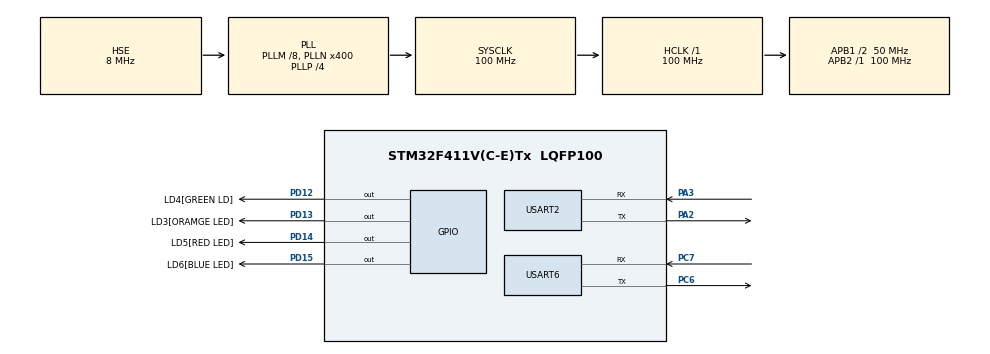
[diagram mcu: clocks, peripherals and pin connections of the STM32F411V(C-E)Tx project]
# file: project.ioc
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Dma.Request0=USART2_RX
Dma.Request1=USART2_TX
Dma.USART2_RX.0.Direction=DMA_PERIPH_TO_MEMORY
Dma.USART2_RX.0.FIFOMode=DMA_FIFOMODE_DISABLE
Dma.USART2_RX.0.Instance=DMA1_Stream5
Dma.USART2_RX.0.MemDataAlignment=DMA_MDATAALIGN_BYTE
Dma.USART2_RX.0.MemInc=DMA_MINC_ENABLE
Dma.USART2_RX.0.Mode=DMA_NORMAL
Dma.USART2_RX.0.PeriphDataAlignment=DMA_PDATAALIGN_BYTE
Dma.USART2_RX.0.PeriphInc=DMA_PINC_DISABLE
Dma.USART2_RX.0.Priority=DMA_PRIORITY_LOW
Dma.USART2_TX.1.Direction=DMA_MEMORY_TO_PERIPH
Dma.USART2_TX.1.FIFOMode=DMA_FIFOMODE_DISABLE
Dma.USART2_TX.1.Instance=DMA1_Stream6
Dma.USART2_TX.1.MemDataAlignment=DMA_MDATAALIGN_BYTE
Dma.USART2_TX.1.MemInc=DMA_MINC_ENABLE
Dma.USART2_TX.1.Mode=DMA_NORMAL
Dma.USART2_TX.1.PeriphDataAlignment=DMA_PDATAALIGN_BYTE
Dma.USART2_TX.1.PeriphInc=DMA_PINC_DISABLE
Dma.USART2_TX.1.Priority=DMA_PRIORITY_LOW
Mcu.Family=STM32F4
Mcu.Name=STM32F411V(C-E)Tx
Mcu.Package=LQFP100
NVIC.DMA1_Stream5_IRQn=true\:0\:0\:false\:false\:true\:false
NVIC.DMA1_Stream6_IRQn=true\:0\:0\:false\:false\:true\:false
NVIC.PriorityGroup=NVIC_PRIORITYGROUP_0
NVIC.USART2_IRQn=true\:0\:0\:false\:false\:true\:true
NVIC.USART6_IRQn=true\:0\:0\:false\:false\:true\:true
PA2.Mode=Asynchronous
PA2.Signal=USART2_TX
PA3.Mode=Asynchronous
PA3.Signal=USART2_RX
PC6.Mode=Asynchronous
PC6.Signal=USART6_TX
PC7.Mode=Asynchronous
PC7.Signal=USART6_RX
PD12.GPIO_Label=LD4[GREEN LD]
PD12.Signal=GPIO_Output
PD13.GPIO_Label=LD3[ORAMGE LED]
PD13.Signal=GPIO_Output
PD14.GPIO_Label=LD5[RED LED]
PD14.Signal=GPIO_Output
PD15.GPIO_Label=LD6[BLUE LED]
PD15.Signal=GPIO_Output
PH0\ -\ OSC_IN.Mode=HSE-External-Oscillator
PH0\ -\ OSC_IN.Signal=RCC_OSC_IN
PH1\ -\ OSC_OUT.Mode=HSE-External-Oscillator
PH1\ -\ OSC_OUT.Signal=RCC_OSC_OUT
ProjectManager.HeapSize=0x200
ProjectManager.StackSize=0x400
ProjectManager.TargetToolchain=Other Toolchains (GPDSC)
RCC.48MHZClocksFreq_Value=50000000
RCC.AHBFreq_Value=100000000
RCC.APB1CLKDivider=RCC_HCLK_DIV2
RCC.APB1Freq_Value=50000000
RCC.APB1TimFreq_Value=100000000
RCC.APB2Freq_Value=100000000
RCC.APB2TimFreq_Value=100000000
RCC.CortexFreq_Value=100000000
RCC.HCLKFreq_Value=100000000
RCC.HSE_VALUE=8000000
RCC.HSI_VALUE=16000000
RCC.LSE_VALUE=32768
RCC.PLLI2SM=5
RCC.PLLI2SN=200
RCC.PLLM=8
RCC.PLLN=400
RCC.PLLP=RCC_PLLP_DIV4
RCC.PLLQ=8
RCC.PLLSourceVirtual=RCC_PLLSOURCE_HSE
RCC.SYSCLKFreq_VALUE=100000000
RCC.SYSCLKSource=RCC_SYSCLKSOURCE_PLLCLK
RCC.VCOOutputFreq_Value=400000000
USART2.VirtualMode=VM_ASYNC
USART6.VirtualMode=VM_ASYNC
board=STM32F411E-DISCO

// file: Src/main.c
/**
  ******************************************************************************
  * File Name          : main.c
  * Description        : Main program body
  ******************************************************************************
  ** This notice applies to any and all portions of this file
  * that are not between comment pairs USER CODE BEGIN and
  * USER CODE END. Other portions of this file, whether
  * inserted by the user or by software development tools
  * are owned by their respective copyright owners.
  *
  * COPYRIGHT(c) 2017 STMicroelectronics
  *
  * Redistribution and use in source and binary forms, with or without modification,
  * are permitted provided that the following conditions are met:
  *   1. Redistributions of source code must retain the above copyright notice,
  *      this list of conditions and the following disclaimer.
  *   2. Redistributions in binary form must reproduce the above copyright notice,
  *      this list of conditions and the following disclaimer in the documentation
  *      and/or other materials provided with the distribution.
  *   3. Neither the name of STMicroelectronics nor the names of its contributors
  *      may be used to endorse or promote products derived from this software
  *      without specific prior written permission.
  *
  * THIS SOFTWARE IS PROVIDED BY THE COPYRIGHT HOLDERS AND CONTRIBUTORS "AS IS"
  * AND ANY EXPRESS OR IMPLIED WARRANTIES, INCLUDING, BUT NOT LIMITED TO, THE
  * IMPLIED WARRANTIES OF MERCHANTABILITY AND FITNESS FOR A PARTICULAR PURPOSE ARE
  * DISCLAIMED. IN NO EVENT SHALL THE COPYRIGHT HOLDER OR CONTRIBUTORS BE LIABLE
  * FOR ANY DIRECT, INDIRECT, INCIDENTAL, SPECIAL, EXEMPLARY, OR CONSEQUENTIAL
  * DAMAGES (INCLUDING, BUT NOT LIMITED TO, PROCUREMENT OF SUBSTITUTE GOODS OR
  * SERVICES; LOSS OF USE, DATA, OR PROFITS; OR BUSINESS INTERRUPTION) HOWEVER
  * CAUSED AND ON ANY THEORY OF LIABILITY, WHETHER IN CONTRACT, STRICT LIABILITY,
  * OR TORT (INCLUDING NEGLIGENCE OR OTHERWISE) ARISING IN ANY WAY OUT OF THE USE
  * OF THIS SOFTWARE, EVEN IF ADVISED OF THE POSSIBILITY OF SUCH DAMAGE.
  *
  ******************************************************************************
  */

#include "main.h"
#include "stm32f4xx_hal.h"
#include "GSM_7100.h"
#include "UARTXinOu.h"

UART_HandleTypeDef huart1;
UART_HandleTypeDef huart2;
UART_HandleTypeDef huart6;
DMA_HandleTypeDef hdma_usart2_rx;
DMA_HandleTypeDef hdma_usart2_tx;

/* USER CODE BEGIN PV */
/* Private variables ---------------------------------------------------------*/
#define		_AT_										"AT\r"
#define  temperature1 "EdgeFS1/1wire/temperature/th1"
#define  temperature2 "EdgeFS1/1wire/temperature/th2"

char pub = 123;

char ClientID[] = "EdgeFS1";

mqtt_tab mqtt[10] = {
	{ "EdgeFS1/1wire/temperature/th1", "mmm", "%+07.2f", 0.0 },
	{ "EdgeFS1/1wire/temperature/th2", "hhh", "%+07.2f", 0.0 },
	{ "EdgeFS1/1wire/temperature/th3", "", "%+07.2f", 0.0 },
	{ "EdgeFS1/ADI/chan1/voltage", "", "%06.3f", 0.0 },
	{ "EdgeFS1/ADI/chan2/current", "", "%06.3f", 0.0 },
	{ "EdgeFS1/ADI/chan3/logical", "", "%1.0f", 0.0 },
	{ "EdgeFS1/ADI/chan4/logical", "", "%1.0f", 0.0 },
	{ "EdgeFS1/RS232/dmm/voltage", "", "%06.2f", 0.0 },
	{ "EdgeFS1/DO/chan1", "", "%1.0f", 0.0 },
	{ "EdgeFS1/DO/chan3", "", "%1.0f", 0.0 }
};
/* USER CODE END PV */

void SystemClock_Config(void);
static void MX_GPIO_Init(void);
static void MX_DMA_Init(void);
static void MX_USART2_UART_Init(void);
static void MX_USART6_UART_Init(void);

/* USER CODE BEGIN PFP */
/* Private function prototypes -----------------------------------------------*/

/* USER CODE END PFP */

/* USER CODE BEGIN 0 */
void HAL_UART_RxCpltCallback(UART_HandleTypeDef *huart);

char topic[] = "EdgeFS1/1wire/temperature/th1";
unsigned char AT1[] = "AT\r";

/* USER CODE END 0 */

int main(void)
{
	char a = 123;

  /* MCU Configuration----------------------------------------------------------*/

  /* Reset of all peripherals, Initializes the Flash interface and the Systick. */
  HAL_Init();

  /* Configure the system clock */
  SystemClock_Config();

  /* Initialize all configured peripherals */
  MX_GPIO_Init();
  MX_DMA_Init();
  MX_USART2_UART_Init();
  MX_USART6_UART_Init();

  /* USER CODE BEGIN 2 */

	__HAL_UART_ENABLE_IT(&huart2, UART_IT_RXNE);
	__HAL_UART_ENABLE_IT(&huart6, UART_IT_TC);   // ENABLES INTERRPUT WHEN RECEIVE BUFFER IS NOT EMPTY
//	HAL_UART_Receive_IT(&huart6, Rx_data, 1);
	/* USER CODE END 2 */

	HAL_GPIO_WritePin(GPIOC, GPIO_PIN_1, GPIO_PIN_SET);
	HAL_Delay(300);
	HAL_GPIO_WritePin(GPIOC, GPIO_PIN_1, GPIO_PIN_RESET);
	HAL_Delay(100);

	init_quectel();

	//Only if TCP socket is open successfully it will come of of this function.

	//connect("ABCDEf"); // cLIENT ID for connect packet

  /* USER CODE END 2 */

	//Publishpkt("inTopic", "jjjjj");   //

	//Publishpkt("inTopic", "cfh");
	//Mqtt_subscribe("AA");
  /* Infinite loop */

	connect(ClientID);

	flush_buf();

	flush_buf();
	//*main_rx_buf[0] = '\0';
	//flush_buf();
	//Mqtt_subscribe("aa");
	while (1)
	{
		//a=Publishpkt_num(temperature1, pub);
		//Publishpkt_num(&topic, );

		for(int i = 0 ; i < 2 ; i++)
		{
			a= Publishpkt(i);
		}

  /* USER CODE BEGIN 3 */

	}

}

/** System Clock Configuration
*/
void SystemClock_Config(void)
{

  RCC_OscInitTypeDef RCC_OscInitStruct;
  RCC_ClkInitTypeDef RCC_ClkInitStruct;

    /**Configure the main internal regulator output voltage
    */
	__HAL_RCC_PWR_CLK_ENABLE();

  __HAL_PWR_VOLTAGESCALING_CONFIG(PWR_REGULATOR_VOLTAGE_SCALE1);

    /**Initializes the CPU, AHB and APB busses clocks
    */
  RCC_OscInitStruct.OscillatorType = RCC_OSCILLATORTYPE_HSE;
  RCC_OscInitStruct.HSEState = RCC_HSE_ON;
  RCC_OscInitStruct.PLL.PLLState = RCC_PLL_ON;
  RCC_OscInitStruct.PLL.PLLSource = RCC_PLLSOURCE_HSE;
  RCC_OscInitStruct.PLL.PLLM = 8;
  RCC_OscInitStruct.PLL.PLLN = 400;
  RCC_OscInitStruct.PLL.PLLP = RCC_PLLP_DIV4;
  RCC_OscInitStruct.PLL.PLLQ = 8;
  if (HAL_RCC_OscConfig(&RCC_OscInitStruct) != HAL_OK)
  {
    _Error_Handler(__FILE__, __LINE__);
  }

    /**Initializes the CPU, AHB and APB busses clocks
    */
  RCC_ClkInitStruct.ClockType = RCC_CLOCKTYPE_HCLK|RCC_CLOCKTYPE_SYSCLK
                              |RCC_CLOCKTYPE_PCLK1|RCC_CLOCKTYPE_PCLK2;
  RCC_ClkInitStruct.SYSCLKSource = RCC_SYSCLKSOURCE_PLLCLK;
  RCC_ClkInitStruct.AHBCLKDivider = RCC_SYSCLK_DIV1;
  RCC_ClkInitStruct.APB1CLKDivider = RCC_HCLK_DIV2;
  RCC_ClkInitStruct.APB2CLKDivider = RCC_HCLK_DIV1;

  if (HAL_RCC_ClockConfig(&RCC_ClkInitStruct, FLASH_LATENCY_3) != HAL_OK)
  {
    _Error_Handler(__FILE__, __LINE__);
  }

    /**Configure the Systick interrupt time
    */
  HAL_SYSTICK_Config(HAL_RCC_GetHCLKFreq()/1000);

    /**Configure the Systick
    */
  HAL_SYSTICK_CLKSourceConfig(SYSTICK_CLKSOURCE_HCLK);

  /* SysTick_IRQn interrupt configuration */
  HAL_NVIC_SetPriority(SysTick_IRQn, 0, 0);
}

/* USART2 init function */
static void MX_USART2_UART_Init(void)
{

  huart2.Instance = USART2;
  huart2.Init.BaudRate = 115200;
  huart2.Init.WordLength = UART_WORDLENGTH_8B;
  huart2.Init.StopBits = UART_STOPBITS_1;
  huart2.Init.Parity = UART_PARITY_NONE;
  huart2.Init.Mode = UART_MODE_TX_RX;
  huart2.Init.HwFlowCtl = UART_HWCONTROL_NONE;
  huart2.Init.OverSampling = UART_OVERSAMPLING_16;
  if (HAL_UART_Init(&huart2) != HAL_OK)
  {
    _Error_Handler(__FILE__, __LINE__);
  }

}

/* USART6 init function */
static void MX_USART6_UART_Init(void)
{

  huart6.Instance = USART6;
  huart6.Init.BaudRate = 115200;
  huart6.Init.WordLength = UART_WORDLENGTH_8B;
  huart6.Init.StopBits = UART_STOPBITS_1;
  huart6.Init.Parity = UART_PARITY_NONE;
  huart6.Init.Mode = UART_MODE_TX_RX;
  huart6.Init.HwFlowCtl = UART_HWCONTROL_NONE;
  huart6.Init.OverSampling = UART_OVERSAMPLING_16;
  if (HAL_UART_Init(&huart6) != HAL_OK)
  {
    _Error_Handler(__FILE__, __LINE__);
  }

}

static void MX_DMA_Init(void)
{
  /* DMA controller clock enable */
  __HAL_RCC_DMA1_CLK_ENABLE();

  /* DMA interrupt init */
  /* DMA1_Stream5_IRQn interrupt configuration */
  HAL_NVIC_SetPriority(DMA1_Stream5_IRQn, 0, 0);
  HAL_NVIC_EnableIRQ(DMA1_Stream5_IRQn);
  /* DMA1_Stream6_IRQn interrupt configuration */
  HAL_NVIC_SetPriority(DMA1_Stream6_IRQn, 0, 0);
  HAL_NVIC_EnableIRQ(DMA1_Stream6_IRQn);

}

/** Configure pins as
        * Analog
        * Input
        * Output
        * EVENT_OUT
        * EXTI
*/
static void MX_GPIO_Init(void)
{

  GPIO_InitTypeDef GPIO_InitStruct;

  /* GPIO Ports Clock Enable */
  __HAL_RCC_GPIOH_CLK_ENABLE();
  __HAL_RCC_GPIOA_CLK_ENABLE();
  __HAL_RCC_GPIOD_CLK_ENABLE();
  __HAL_RCC_GPIOC_CLK_ENABLE();

  /*Configure GPIO pin Output Level */
  //HAL_GPIO_WritePin(GPIOD, LD4_Pin|LD3_Pin|LD5_Pin|LD6_Pin, GPIO_PIN_RESET);

  /*Configure GPIO pins : LD4_Pin LD3_Pin LD5_Pin LD6_Pin */
  //GPIO_InitStruct.Pin = LD4_Pin|LD3_Pin|LD5_Pin|LD6_Pin;
  //GPIO_InitStruct.Mode = GPIO_MODE_OUTPUT_PP;
  //GPIO_InitStruct.Pull = GPIO_NOPULL;
  //GPIO_InitStruct.Speed = GPIO_SPEED_FREQ_LOW;
  //HAL_GPIO_Init(GPIOD, &GPIO_InitStruct);
	//GPIO_InitTypeDef GPIO_InitStruct;

	HAL_GPIO_WritePin(GPIOC, GPIO_PIN_1 | GPIO_PIN_2, GPIO_PIN_RESET);
	/*Configure GPIO pins : PC1 PC2 */
	GPIO_InitStruct.Pin = GPIO_PIN_1 | GPIO_PIN_2;
	GPIO_InitStruct.Mode = GPIO_MODE_OUTPUT_PP;
	GPIO_InitStruct.Pull = GPIO_NOPULL;
	GPIO_InitStruct.Speed = GPIO_SPEED_FREQ_LOW;
	HAL_GPIO_Init(GPIOC, &GPIO_InitStruct);

}

void _Error_Handler(char * file, int line)
{
	while (1)
	{
	}
}

/************************ (C) COPYRIGHT STMicroelectronics *****END OF FILE****/
